VERSION 5.7 ;
  NOWIREEXTENSIONATPIN ON ;
  DIVIDERCHAR "/" ;
  BUSBITCHARS "[]" ;
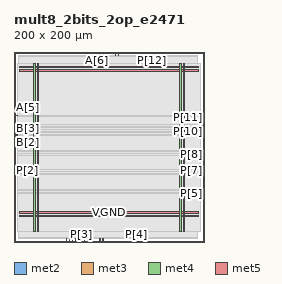
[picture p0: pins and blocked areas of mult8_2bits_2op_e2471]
MACRO mult8_2bits_2op_e2471
  CLASS BLOCK ;
  FOREIGN mult8_2bits_2op_e2471 ;
  ORIGIN 0.000 0.000 ;
  SIZE 200.000 BY 200.000 ;
  PIN A[0]
    DIRECTION INPUT ;
    USE SIGNAL ;
    ANTENNAGATEAREA 0.495000 ;
    PORT
      LAYER met2 ;
        RECT 80.590 0.000 80.870 4.000 ;
    END
  END A[0]
  PIN A[1]
    DIRECTION INPUT ;
    USE SIGNAL ;
    ANTENNAGATEAREA 0.126000 ;
    PORT
      LAYER met2 ;
        RECT 61.270 0.000 61.550 4.000 ;
    END
  END A[1]
  PIN A[2]
    DIRECTION INPUT ;
    USE SIGNAL ;
    ANTENNAGATEAREA 0.742500 ;
    PORT
      LAYER met2 ;
        RECT 77.370 0.000 77.650 4.000 ;
    END
  END A[2]
  PIN A[3]
    DIRECTION INPUT ;
    USE SIGNAL ;
    ANTENNAGATEAREA 0.213000 ;
    PORT
      LAYER met2 ;
        RECT 74.150 0.000 74.430 4.000 ;
    END
  END A[3]
  PIN A[4]
    DIRECTION INPUT ;
    USE SIGNAL ;
    ANTENNAGATEAREA 0.126000 ;
    PORT
      LAYER met2 ;
        RECT 54.830 0.000 55.110 4.000 ;
    END
  END A[4]
  PIN A[5]
    DIRECTION INPUT ;
    USE SIGNAL ;
    ANTENNAGATEAREA 0.213000 ;
    PORT
      LAYER met3 ;
        RECT 0.000 132.640 4.000 133.240 ;
    END
  END A[5]
  PIN A[6]
    DIRECTION INPUT ;
    USE SIGNAL ;
    ANTENNAGATEAREA 0.196500 ;
    PORT
      LAYER met2 ;
        RECT 87.030 196.000 87.310 200.000 ;
    END
  END A[6]
  PIN A[7]
    DIRECTION INPUT ;
    USE SIGNAL ;
    ANTENNAGATEAREA 0.196500 ;
    PORT
      LAYER met2 ;
        RECT 93.470 196.000 93.750 200.000 ;
    END
  END A[7]
  PIN B[0]
    DIRECTION INPUT ;
    USE SIGNAL ;
    ANTENNAGATEAREA 0.213000 ;
    PORT
      LAYER met2 ;
        RECT 64.490 0.000 64.770 4.000 ;
    END
  END B[0]
  PIN B[1]
    DIRECTION INPUT ;
    USE SIGNAL ;
    ANTENNAGATEAREA 0.196500 ;
    PORT
      LAYER met2 ;
        RECT 67.710 0.000 67.990 4.000 ;
    END
  END B[1]
  PIN B[2]
    DIRECTION INPUT ;
    USE SIGNAL ;
    ANTENNAGATEAREA 0.495000 ;
    PORT
      LAYER met3 ;
        RECT 0.000 112.240 4.000 112.840 ;
    END
  END B[2]
  PIN B[3]
    DIRECTION INPUT ;
    USE SIGNAL ;
    ANTENNAGATEAREA 0.495000 ;
    PORT
      LAYER met3 ;
        RECT 0.000 119.040 4.000 119.640 ;
    END
  END B[3]
  PIN B[4]
    DIRECTION INPUT ;
    USE SIGNAL ;
    ANTENNAGATEAREA 0.213000 ;
    PORT
      LAYER met2 ;
        RECT 93.470 0.000 93.750 4.000 ;
    END
  END B[4]
  PIN B[5]
    DIRECTION INPUT ;
    USE SIGNAL ;
    ANTENNAGATEAREA 0.196500 ;
    PORT
      LAYER met2 ;
        RECT 90.250 0.000 90.530 4.000 ;
    END
  END B[5]
  PIN B[6]
    DIRECTION INPUT ;
    USE SIGNAL ;
    ANTENNAGATEAREA 0.495000 ;
    PORT
      LAYER met2 ;
        RECT 109.570 196.000 109.850 200.000 ;
    END
  END B[6]
  PIN B[7]
    DIRECTION INPUT ;
    USE SIGNAL ;
    ANTENNAGATEAREA 0.213000 ;
    PORT
      LAYER met2 ;
        RECT 106.350 196.000 106.630 200.000 ;
    END
  END B[7]
  PIN P[0]
    DIRECTION OUTPUT ;
    USE SIGNAL ;
    ANTENNADIFFAREA 0.445500 ;
    PORT
      LAYER met3 ;
        RECT 0.000 71.440 4.000 72.040 ;
    END
  END P[0]
  PIN P[10]
    DIRECTION OUTPUT ;
    USE SIGNAL ;
    ANTENNADIFFAREA 1.336500 ;
    PORT
      LAYER met3 ;
        RECT 196.000 115.640 200.000 116.240 ;
    END
  END P[10]
  PIN P[11]
    DIRECTION OUTPUT ;
    USE SIGNAL ;
    ANTENNADIFFAREA 1.336500 ;
    PORT
      LAYER met3 ;
        RECT 196.000 122.440 200.000 123.040 ;
    END
  END P[11]
  PIN P[12]
    DIRECTION OUTPUT ;
    USE SIGNAL ;
    ANTENNADIFFAREA 1.336500 ;
    PORT
      LAYER met2 ;
        RECT 144.990 196.000 145.270 200.000 ;
    END
  END P[12]
  PIN P[13]
    DIRECTION OUTPUT ;
    USE SIGNAL ;
    ANTENNADIFFAREA 1.336500 ;
    PORT
      LAYER met2 ;
        RECT 138.550 196.000 138.830 200.000 ;
    END
  END P[13]
  PIN P[14]
    DIRECTION OUTPUT ;
    USE SIGNAL ;
    ANTENNADIFFAREA 1.336500 ;
    PORT
      LAYER met2 ;
        RECT 96.690 196.000 96.970 200.000 ;
    END
  END P[14]
  PIN P[15]
    DIRECTION OUTPUT ;
    USE SIGNAL ;
    ANTENNADIFFAREA 1.336500 ;
    PORT
      LAYER met2 ;
        RECT 90.250 196.000 90.530 200.000 ;
    END
  END P[15]
  PIN P[1]
    DIRECTION OUTPUT ;
    USE SIGNAL ;
    ANTENNADIFFAREA 0.445500 ;
    PORT
      LAYER met2 ;
        RECT 58.050 0.000 58.330 4.000 ;
    END
  END P[1]
  PIN P[2]
    DIRECTION OUTPUT ;
    USE SIGNAL ;
    ANTENNADIFFAREA 0.445500 ;
    PORT
      LAYER met3 ;
        RECT 0.000 74.840 4.000 75.440 ;
    END
  END P[2]
  PIN P[3]
    DIRECTION OUTPUT ;
    USE SIGNAL ;
    ANTENNADIFFAREA 0.445500 ;
    PORT
      LAYER met2 ;
        RECT 70.930 0.000 71.210 4.000 ;
    END
  END P[3]
  PIN P[4]
    DIRECTION OUTPUT ;
    USE SIGNAL ;
    ANTENNADIFFAREA 0.445500 ;
    PORT
      LAYER met2 ;
        RECT 128.890 0.000 129.170 4.000 ;
    END
  END P[4]
  PIN P[5]
    DIRECTION OUTPUT ;
    USE SIGNAL ;
    ANTENNADIFFAREA 0.445500 ;
    PORT
      LAYER met3 ;
        RECT 196.000 51.040 200.000 51.640 ;
    END
  END P[5]
  PIN P[6]
    DIRECTION OUTPUT ;
    USE SIGNAL ;
    ANTENNADIFFAREA 0.795200 ;
    PORT
      LAYER met3 ;
        RECT 196.000 54.440 200.000 55.040 ;
    END
  END P[6]
  PIN P[7]
    DIRECTION OUTPUT ;
    USE SIGNAL ;
    ANTENNADIFFAREA 1.336500 ;
    PORT
      LAYER met3 ;
        RECT 196.000 74.840 200.000 75.440 ;
    END
  END P[7]
  PIN P[8]
    DIRECTION OUTPUT ;
    USE SIGNAL ;
    ANTENNADIFFAREA 1.336500 ;
    PORT
      LAYER met3 ;
        RECT 196.000 91.840 200.000 92.440 ;
    END
  END P[8]
  PIN P[9]
    DIRECTION OUTPUT ;
    USE SIGNAL ;
    ANTENNADIFFAREA 1.336500 ;
    PORT
      LAYER met3 ;
        RECT 196.000 95.240 200.000 95.840 ;
    END
  END P[9]
  PIN VGND
    DIRECTION INOUT ;
    USE GROUND ;
    PORT
      LAYER met4 ;
        RECT 24.340 10.640 25.940 187.920 ;
    END
    PORT
      LAYER met4 ;
        RECT 177.940 10.640 179.540 187.920 ;
    END
    PORT
      LAYER met5 ;
        RECT 5.280 30.030 194.360 31.630 ;
    END
    PORT
      LAYER met5 ;
        RECT 5.280 183.210 194.360 184.810 ;
    END
  END VGND
  PIN VPWR
    DIRECTION INOUT ;
    USE POWER ;
    PORT
      LAYER met4 ;
        RECT 21.040 10.640 22.640 187.920 ;
    END
    PORT
      LAYER met4 ;
        RECT 174.640 10.640 176.240 187.920 ;
    END
    PORT
      LAYER met5 ;
        RECT 5.280 26.730 194.360 28.330 ;
    END
    PORT
      LAYER met5 ;
        RECT 5.280 179.910 194.360 181.510 ;
    END
  END VPWR
  OBS
      LAYER nwell ;
        RECT 5.330 10.795 194.310 187.870 ;
      LAYER li1 ;
        RECT 5.520 10.795 194.120 187.765 ;
      LAYER met1 ;
        RECT 4.210 10.640 194.120 187.920 ;
      LAYER met2 ;
        RECT 4.230 195.720 86.750 196.000 ;
        RECT 87.590 195.720 89.970 196.000 ;
        RECT 90.810 195.720 93.190 196.000 ;
        RECT 94.030 195.720 96.410 196.000 ;
        RECT 97.250 195.720 106.070 196.000 ;
        RECT 106.910 195.720 109.290 196.000 ;
        RECT 110.130 195.720 138.270 196.000 ;
        RECT 139.110 195.720 144.710 196.000 ;
        RECT 145.550 195.720 192.650 196.000 ;
        RECT 4.230 4.280 192.650 195.720 ;
        RECT 4.230 4.000 54.550 4.280 ;
        RECT 55.390 4.000 57.770 4.280 ;
        RECT 58.610 4.000 60.990 4.280 ;
        RECT 61.830 4.000 64.210 4.280 ;
        RECT 65.050 4.000 67.430 4.280 ;
        RECT 68.270 4.000 70.650 4.280 ;
        RECT 71.490 4.000 73.870 4.280 ;
        RECT 74.710 4.000 77.090 4.280 ;
        RECT 77.930 4.000 80.310 4.280 ;
        RECT 81.150 4.000 89.970 4.280 ;
        RECT 90.810 4.000 93.190 4.280 ;
        RECT 94.030 4.000 128.610 4.280 ;
        RECT 129.450 4.000 192.650 4.280 ;
      LAYER met3 ;
        RECT 3.990 133.640 196.000 187.845 ;
        RECT 4.400 132.240 196.000 133.640 ;
        RECT 3.990 123.440 196.000 132.240 ;
        RECT 3.990 122.040 195.600 123.440 ;
        RECT 3.990 120.040 196.000 122.040 ;
        RECT 4.400 118.640 196.000 120.040 ;
        RECT 3.990 116.640 196.000 118.640 ;
        RECT 3.990 115.240 195.600 116.640 ;
        RECT 3.990 113.240 196.000 115.240 ;
        RECT 4.400 111.840 196.000 113.240 ;
        RECT 3.990 96.240 196.000 111.840 ;
        RECT 3.990 94.840 195.600 96.240 ;
        RECT 3.990 92.840 196.000 94.840 ;
        RECT 3.990 91.440 195.600 92.840 ;
        RECT 3.990 75.840 196.000 91.440 ;
        RECT 4.400 74.440 195.600 75.840 ;
        RECT 3.990 72.440 196.000 74.440 ;
        RECT 4.400 71.040 196.000 72.440 ;
        RECT 3.990 55.440 196.000 71.040 ;
        RECT 3.990 54.040 195.600 55.440 ;
        RECT 3.990 52.040 196.000 54.040 ;
        RECT 3.990 50.640 195.600 52.040 ;
        RECT 3.990 10.715 196.000 50.640 ;
  END
END mult8_2bits_2op_e2471
END LIBRARY

